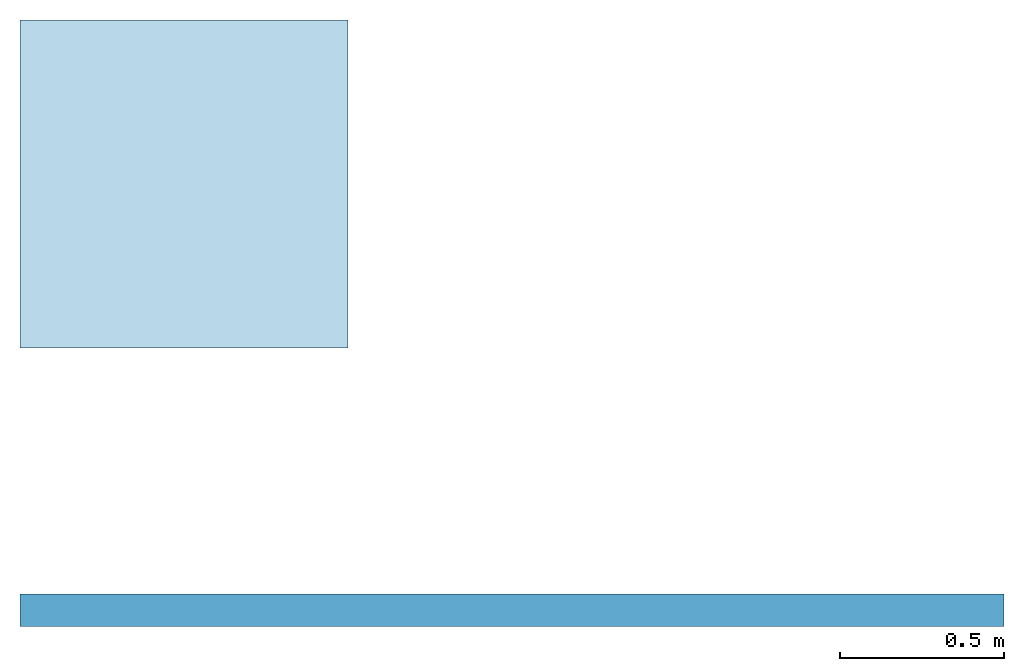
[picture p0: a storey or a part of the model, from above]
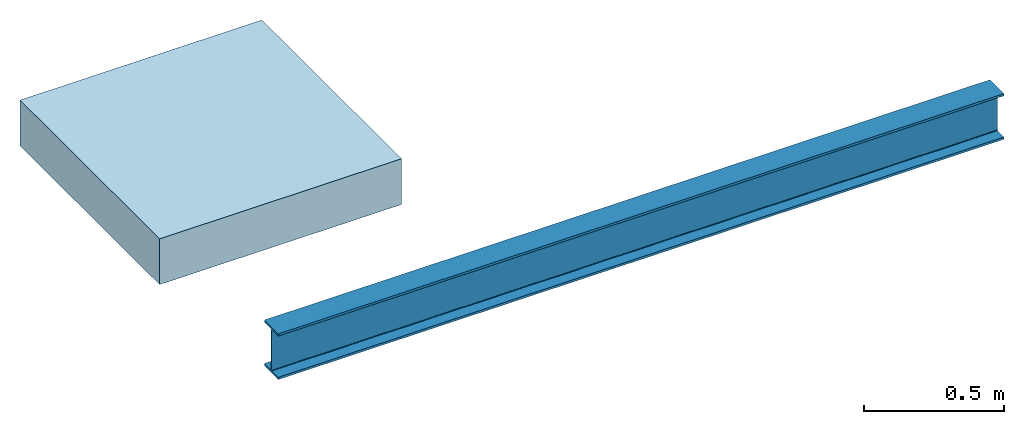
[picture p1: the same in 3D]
Properties of the parts of a building model (IFC4)

# File
Description: ViewDefinition[DesignTransferView]
File name: printing with materials.ifc
Time: 2024-06-13T12:31:20-05:00
Written by: IfcOpenShell v0.7.0-c7830e9e5
Made in: BlenderBIM 0.0.240605-cfd0ed6
Authorization: Nobody

# IfcProject, My Project
Document: MY STOREY PLAN; PLAN_VIEW

# IfcAnnotation: DRAWING (2)
EPset_Drawing - TargetView: PLAN_VIEW; Scale: 1/96; HumanScale: 1/8"=1'-0"; HasUnderlay: yes; HasLinework: yes; HasAnnotation: yes; GlobalReferencing: yes; Stylesheet: drawings/assets/default.css; Markers: drawings/assets/markers.svg; Symbols: drawings/assets/symbols.svg; Patterns: drawings/assets/patterns.svg; ShadingStyles: drawings/assets/shading_styles.json; CurrentShadingStyle: Blender Default
Name | Document | Group
MY STOREY PLAN | X drawings/MY STOREY PLAN.svg | MY STOREY PLAN
PLAN_VIEW | X drawings/PLAN_VIEW.svg | PLAN_VIEW

# IfcBeam: B1, Beam
In: My Storey
Type - Material: Corten Steel Beam
EPset_Parametric - Engine: BlenderBIM.DumbProfile

# IfcSlab: FLR150, Slab
In: My Storey
Type - Material: Concrete Floor 0.656168 ft
EPset_Parametric - Engine: BlenderBIM.DumbLayer3

# IfcBeamType, no part of this type: B2
Material: Unknown

# IfcColumnType, no part of this type: C1
Material: Unknown

# IfcColumnType, no part of this type: C2
Material: Unknown

# IfcColumnType, no part of this type: C3
Material: Unknown

# IfcCoveringType, no part of this type: COV10
Material: Unknown 0.0328084 ft

# IfcCoveringType, no part of this type: COV20
Material: Unknown 0.0656168 ft
EPset_Parametric - LayerSetDirection: AXIS2

# IfcCoveringType, no part of this type: COV30
Material: Unknown 0.0984252 ft
EPset_Parametric - LayerSetDirection: AXIS3

# IfcPileType, no part of this type: P1
Material: Unknown

# IfcRampType, no part of this type: RAM200
Material: Unknown 0.656168 ft

# IfcSlabType, no part of this type: FLR250
Material: Unknown 0.984252 ft

# IfcTypeProduct, no part of this type: CONTROL-POINT
ApplicableOccurrence: IfcAnnotation/SYMBOL
EPset_Annotation - Symbol: control-point

# IfcTypeProduct, no part of this type: DASHED
ApplicableOccurrence: IfcAnnotation/LINEWORK
EPset_Annotation - Classes: dashed

# IfcTypeProduct, no part of this type: DOOR-TAG
ApplicableOccurrence: IfcAnnotation/TEXT
EPset_Annotation - Symbol: door-tag

# IfcTypeProduct, no part of this type: FINE
ApplicableOccurrence: IfcAnnotation/LINEWORK
EPset_Annotation - Classes: fine

# IfcTypeProduct, no part of this type: MATERIAL-TAG
ApplicableOccurrence: IfcAnnotation/TEXT
EPset_Annotation - Symbol: rectangle-tag

# IfcTypeProduct, no part of this type: MEDIUM
ApplicableOccurrence: IfcAnnotation/LINEWORK
EPset_Annotation - Classes: medium

# IfcTypeProduct, no part of this type: NAME-TAG
ApplicableOccurrence: IfcAnnotation/TEXT
EPset_Annotation - Symbol: capsule-tag

# IfcTypeProduct, no part of this type: SETOUT-POINT
ApplicableOccurrence: IfcAnnotation/SYMBOL
EPset_Annotation - Symbol: setout-point

# IfcTypeProduct, no part of this type: SETOUT-TAG
ApplicableOccurrence: IfcAnnotation/TEXT
EPset_Annotation - Symbol: setout-tag

# IfcTypeProduct, no part of this type: SPACE-TAG
ApplicableOccurrence: IfcAnnotation/TEXT
EPset_Annotation - Symbol: space-tag

# IfcTypeProduct, no part of this type: STRONG
ApplicableOccurrence: IfcAnnotation/LINEWORK
EPset_Annotation - Classes: strong

# IfcTypeProduct, no part of this type: THICK
ApplicableOccurrence: IfcAnnotation/LINEWORK
EPset_Annotation - Classes: thick

# IfcTypeProduct, no part of this type: THIN
ApplicableOccurrence: IfcAnnotation/LINEWORK
EPset_Annotation - Classes: thin

# IfcTypeProduct, no part of this type: TRAVERSE-POINT
ApplicableOccurrence: IfcAnnotation/SYMBOL
EPset_Annotation - Symbol: traverse-point

# IfcTypeProduct, no part of this type: TYPE-TAG
ApplicableOccurrence: IfcAnnotation/TEXT
EPset_Annotation - Symbol: capsule-tag

# IfcTypeProduct, no part of this type: WINDOW-TAG
ApplicableOccurrence: IfcAnnotation/TEXT
EPset_Annotation - Symbol: window-tag

# IfcWallType, no part of this type: WAL100
Material: Unknown 0.328084 ft

# IfcWallType, no part of this type: WAL200
Material: Unknown 0.656168 ft

# IfcWallType, no part of this type: WAL300
Material: Unknown 0.984252 ft

# IfcWallType, no part of this type: WAL50
Material: Unknown 0.164042 ft
